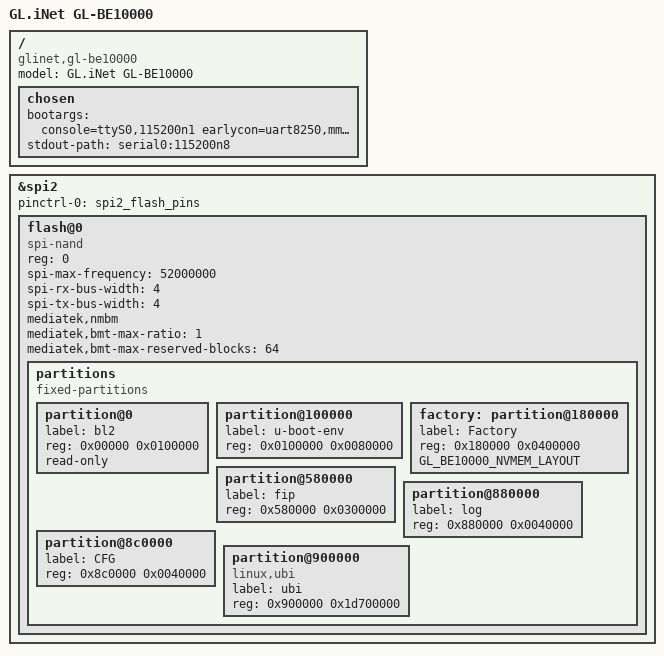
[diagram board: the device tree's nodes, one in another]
// SPDX-License-Identifier: GPL-2.0-or-later OR MIT

/dts-v1/;

#include "mt7987a-glinet-gl-be10000.dtsi"

/ {
	model = "GL.iNet GL-BE10000";
	compatible = "glinet,gl-be10000", "mediatek,mt7987a", "mediatek,mt7987";

	chosen {
		bootargs = "console=ttyS0,115200n1 \
			    earlycon=uart8250,mmio32,0x11000000 \
			    pci=pcie_bus_perf";
		stdout-path = "serial0:115200n8";
	};
};

&spi2 {
	pinctrl-names = "default";
	pinctrl-0 = <&spi2_flash_pins>;
	status = "okay";

	flash@0 {
		compatible = "spi-nand";
		reg = <0>;
		spi-max-frequency = <52000000>;
		spi-rx-bus-width = <4>;
		spi-tx-bus-width = <4>;
		mediatek,nmbm;
		mediatek,bmt-max-ratio = <1>;
		mediatek,bmt-max-reserved-blocks = <64>;

		partitions {
			compatible = "fixed-partitions";
			#address-cells = <1>;
			#size-cells = <1>;

			partition@0 {
				label = "bl2";
				reg = <0x00000 0x0100000>;
				read-only;
			};

			partition@100000 {
				label = "u-boot-env";
				reg = <0x0100000 0x0080000>;
			};

			factory: partition@180000 {
				label = "Factory";
				reg = <0x180000 0x0400000>;

				GL_BE10000_NVMEM_LAYOUT;
			};

			partition@580000 {
				label = "fip";
				reg = <0x580000 0x0300000>;
			};

			partition@880000 {
				label = "log";
				reg = <0x880000 0x0040000>;
			};

			partition@8c0000 {
				label = "CFG";
				reg = <0x8c0000 0x0040000>;
			};

			partition@900000 {
				label = "ubi";
				reg = <0x900000 0x1d700000>;
				compatible = "linux,ubi";
			};
		};
	};
};
